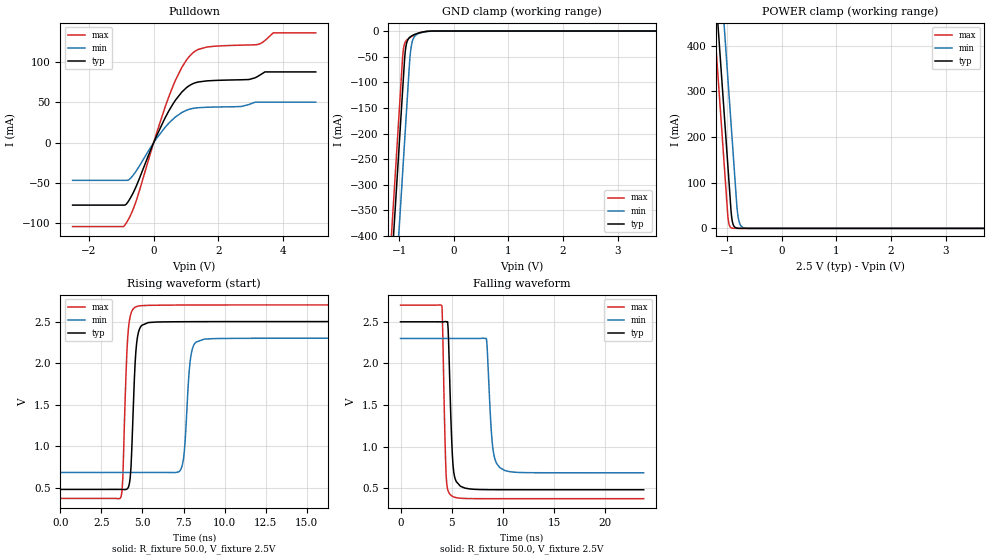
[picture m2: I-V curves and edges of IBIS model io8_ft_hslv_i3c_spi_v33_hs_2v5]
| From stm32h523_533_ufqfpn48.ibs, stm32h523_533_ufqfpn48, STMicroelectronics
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[Model]   io8_ft_hslv_i3c_spi_v33_hs_2v5
Model_type I/O_open_drain
Polarity   Non-Inverting
Enable   Active-Low
| CAP_THRESHOLD on pad IOFT is "UDTCAPC" :
| Rising=20.0% of vddiom   Falling=80.0% of vddiom
| C_comp min and max val. don't necessarily correlate with the min and max pvt
| but are the smallest and greatest pad capacitance found.
| var   typ   min   max
C_comp   3.86841pF  3.83550pF  3.96274pF
|C_comp_pulldown   3.86841pF  3.83550pF  3.96274pF
Vinl = 1.15V
Vinh = 1.35V
Vmeas = 1.25V   | Reference voltage for timing measurements
Cref  = 50.0pF   | Timing specification test load capacitance value
Rref  = 1.0MOhm   | Timing specification test load resistance value
Vref  = 1.375V   | Timing specification test load voltage
[Model Spec]
| TIME_THRESHOLD on pin ZII2CV11 is "CMOS" :
| Rising=40.0% of vdd   Falling=60.0% of vdd
Vinl 978.80000mV 906.80000mV 1.05480V
Vinh 1.39920V 1.29220V 1.48720V
| variable   typ   min   max
[Temperature Range] 25.0 125.0 -40.0
| variable   typ   min   max
[Voltage Range] 2.5V 2.3V 2.7V
| variable   typ   min   max
[POWER Clamp Reference] 2.5V 2.3V 2.7V
| variable   typ   min   max
[GND Clamp Reference] 0V 0V 0V
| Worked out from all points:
|   slope of the pulldown table from 0 to 0.375 V, typ, clamps not added: 11.5 ohm
|   GND clamp passes 1 mA (typ) near -0.52 V on its own axis
|   POWER clamp passes 1 mA (typ) near -0.84 V on its own axis
|   rising waveform, R_fixture 50.0, V_fixture 2.5V: 20-80 % time 253ps typ, 305ps min, 242ps max; typ from 0.481 V to 2.5 V
|   falling waveform, R_fixture 50.0, V_fixture 2.5V: 20-80 % time 336ps typ, 448ps min, 253ps max; typ from 2.5 V to 0.481 V
[POWER Clamp]
-2.5V     2.708A     2.899A     2.597A
-1.23V    548.8mA    740.2mA    437.5mA
-1.16V    429.8mA    621.2mA    318.5mA
-1.12V    361.8mA    553.2mA    250.5mA
-1.03V    208.8mA    400.2mA    97.53mA
-980mV    123.8mA    315.2mA    17.95mA
-920mV    26.3mA     213.2mA    906uA
-880mV    5.543mA    145.2mA    123.7uA
-810mV    363.5uA    33.6mA     3.797uA
-770mV    76.62uA    10.47mA    518.8nA
-700mV    5.026uA    1.361mA    16.09nA
5V        0A         0A         0A
[GND Clamp]
-2.5V     -2.77A     -2.931A    -2.704A
-1.21V    -576.8mA   -738.1mA   -511.3mA
-950mV    -134.8mA   -296.1mA   -69.34mA
-920mV    -83.82mA   -245.1mA   -32.48mA
-900mV    -50.56mA   -211.1mA   -24.02mA
-880mV    -31.31mA   -177.1mA   -19.85mA
-850mV    -18.7mA    -126.1mA   -16.34mA
-800mV    -11.46mA   -46.18mA   -12.45mA
-750mV    -8.203mA   -16.63mA   -9.325mA
-650mV    -4.063mA   -4.987mA   -4.427mA
-360mV    -35.05uA   -165.1uA   -9.564uA
5V        7.96nA     1.282uA    294pA
| variable   typ   min   max
[Pullup Reference] 2.5V 2.3V 2.7V
| variable   typ   min   max
[Pulldown Reference] 0V 0V 0V
[Pulldown]
-2.5V     -77.63mA   -46.85mA   -104.3mA
-870mV    -77.24mA   -46.85mA   -101.4mA
-550mV    -55.3mA    -35.88mA   -73.72mA
90mV      8.401mA    5.299mA    11.79mA
610mV     49.03mA    29.76mA    71.69mA
870mV     62.92mA    37.48mA    93.62mA
1.23V     73.63mA    42.72mA    112.2mA
1.64V     76.78mA    44.01mA    118.8mA
2.7V      78.15mA    44.99mA    121.2mA
3.22V     82.58mA    50.35mA    122.2mA
3.69V     87.93mA    50.35mA    136.5mA
5V        87.93mA    50.35mA    136.5mA
[Ramp]
dV/dt_r 1.21161V/248.6152ps 969.17876mV/301.03751ps 1.39625V/238.23257ps
dV/dt_f 1.21165V/333.92105ps 969.24844mV/447.8085ps 1.39628V/252.6168ps
R_load = 50.0
| Removed startup time: 0s 0s 0s  .
| Removed end time: 23.75ns.
[Rising Waveform]
R_fixture   = 50.0
V_fixture   = 2.5V
V_fixture_min = 2.3V
V_fixture_max = 2.7V
0s        480.6mV    684.6mV    372.9mV
3.7ns     480.6mV    684.6mV    397.6mV
3.8ns     480mV      684.6mV    613.6mV
4.1ns     494.1mV    684.6mV    2.314V
4.3ns     751.3mV    684.6mV    2.598V
4.6ns     2.15V      684.6mV    2.677V
7.35ns    2.498V     727.6mV    2.699V
7.9ns     2.498V     2.015V     2.699V
8.25ns    2.499V     2.251V     2.699V
23.75ns   2.5V       2.3V       2.7V
| Removed startup time: 0s 0s 0s  .
| Removed end time: 23.75ns.
[Falling Waveform]
R_fixture   = 50.0
V_fixture   = 2.5V
V_fixture_min = 2.3V
V_fixture_max = 2.7V
0s        2.5V       2.3V       2.7V
4.05ns    2.499V     2.3V       2.688V
4.45ns    2.503V     2.3V       669.2mV
4.65ns    2.419V     2.3V       466.7mV
4.95ns    1.23V      2.3V       411.4mV
5.45ns    578.1mV    2.3V       385mV
8.4ns     481.8mV    2.291V     373.1mV
8.95ns    481.2mV    1.06V      373mV
9.7ns     480.9mV    745.8mV    373mV
23.75ns   480.6mV    684.6mV    372.9mV
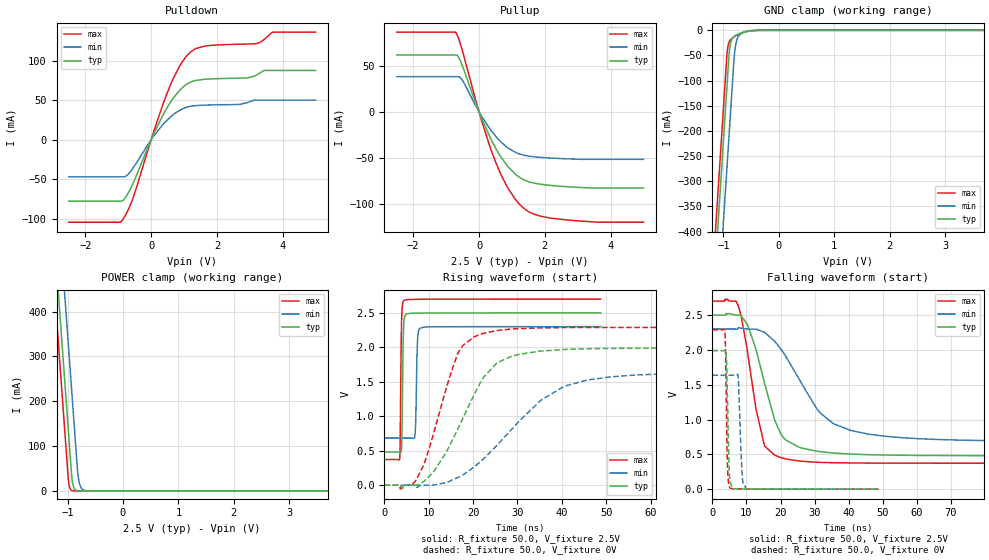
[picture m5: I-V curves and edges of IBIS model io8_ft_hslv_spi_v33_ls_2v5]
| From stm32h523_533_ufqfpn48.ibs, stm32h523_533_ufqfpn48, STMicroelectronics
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[Model]   io8_ft_hslv_spi_v33_ls_2v5
Model_type I/O
Polarity   Non-Inverting
Enable   Active-Low
| CAP_THRESHOLD on pad IOFT is "UDTCAPC" :
| Rising=20.0% of vddiom   Falling=80.0% of vddiom
| C_comp min and max val. don't necessarily correlate with the min and max pvt
| but are the smallest and greatest pad capacitance found.
| var   typ   min   max
C_comp   3.86826pF  3.83550pF  3.96274pF
|C_comp_pullup   2.45390pF  2.33570pF  2.34225pF
|C_comp_pulldown   1.41436pF  1.49980pF  1.62049pF
Vinl = 690.0mV
Vinh = 1.89V
Vmeas = 1.25V   | Reference voltage for timing measurements
Cref  = 50.0pF   | Timing specification test load capacitance value
Rref  = 100.0MOhm   | Timing specification test load resistance value
Vref  = 1.25V   | Timing specification test load voltage
[Model Spec]
| TIME_THRESHOLD on pin ZIV33M is "CMOS" :
| Rising=40.0% of vddiom   Falling=60.0% of vddiom
Vinl 978.80000mV 906.80000mV 1.05480V
Vinh 1.39920V 1.29220V 1.48720V
| variable   typ   min   max
[Temperature Range] 25.0 125.0 -40.0
| variable   typ   min   max
[Voltage Range] 2.5V 2.3V 2.7V
| variable   typ   min   max
[POWER Clamp Reference] 2.5V 2.3V 2.7V
| variable   typ   min   max
[GND Clamp Reference] 0V 0V 0V
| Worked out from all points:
|   slope of the pulldown table from 0 to 0.375 V, typ, clamps not added: 11.5 ohm
|   slope of the pullup table from 0 to 0.375 V, typ, clamps not added: 12.3 ohm
|   GND clamp passes 1 mA (typ) near -0.52 V on its own axis
|   POWER clamp passes 1 mA (typ) near -0.84 V on its own axis
|   rising waveform, R_fixture 50.0, V_fixture 2.5V: 20-80 % time 251ps typ, 301ps min, 240ps max; typ from 0.481 V to 2.5 V
|   falling waveform, R_fixture 50.0, V_fixture 2.5V: 20-80 % time 7.06ns typ, 13.2ns min, 4.9ns max; typ from 2.5 V to 0.481 V
|   rising waveform, R_fixture 50.0, V_fixture 0V: 20-80 % time 9.58ns typ, 15.8ns min, 6.38ns max; typ from 0 V to 1.99 V
|   falling waveform, R_fixture 50.0, V_fixture 0V: 20-80 % time 570ps typ, 766ps min, 453ps max; typ from 1.99 V to 0 V
[POWER Clamp]
-2.5V     2.708A     2.899A     2.597A
-1.23V    548.8mA    740.2mA    437.5mA
-1.16V    429.8mA    621.2mA    318.5mA
-1.12V    361.8mA    553.2mA    250.5mA
-1.03V    208.8mA    400.2mA    97.53mA
-980mV    123.8mA    315.2mA    17.95mA
-920mV    26.3mA     213.2mA    906uA
-880mV    5.543mA    145.2mA    123.7uA
-810mV    363.5uA    33.6mA     3.797uA
-770mV    76.62uA    10.47mA    518.8nA
-700mV    5.026uA    1.361mA    16.09nA
5V        0A         0A         0A
[GND Clamp]
-2.5V     -2.77A     -2.931A    -2.704A
-1.21V    -576.8mA   -738.1mA   -511.3mA
-950mV    -134.8mA   -296.1mA   -69.34mA
-920mV    -83.82mA   -245.1mA   -32.48mA
-900mV    -50.56mA   -211.1mA   -24.02mA
-880mV    -31.31mA   -177.1mA   -19.85mA
-850mV    -18.7mA    -126.1mA   -16.34mA
-800mV    -11.46mA   -46.18mA   -12.45mA
-750mV    -8.203mA   -16.63mA   -9.325mA
-650mV    -4.063mA   -4.987mA   -4.427mA
-360mV    -35.05uA   -165.1uA   -9.564uA
5V        7.96nA     1.281uA    294pA
| variable   typ   min   max
[Pullup Reference] 2.5V 2.3V 2.7V
| variable   typ   min   max
[Pulldown Reference] 0V 0V 0V
[Pullup]
-2.5V     61.52mA    38.03mA    86.31mA
-700mV    61.52mA    38.03mA    85.53mA
-620mV    58.98mA    38.03mA    79.33mA
-510mV    50.24mA    34.32mA    66.72mA
90mV      -7.98mA    -5.461mA   -10.94mA
510mV     -39.75mA   -26.71mA   -54.98mA
870mV     -59.15mA   -39.06mA   -82.32mA
1.13V     -68.49mA   -44.46mA   -96.16mA
1.38V     -74.01mA   -47.22mA   -105.1mA
1.86V     -78.47mA   -49.41mA   -113mA
2.42V     -80.56mA   -50.6mA    -116.3mA
5V        -82.59mA   -51.55mA   -119.6mA
[Pulldown]
-2.5V     -77.63mA   -46.85mA   -104.3mA
-870mV    -77.24mA   -46.85mA   -101.4mA
-550mV    -55.3mA    -35.88mA   -73.72mA
90mV      8.401mA    5.299mA    11.79mA
610mV     49.03mA    29.75mA    71.69mA
870mV     62.92mA    37.48mA    93.62mA
1.23V     73.63mA    42.72mA    112.2mA
1.64V     76.78mA    44.01mA    118.8mA
2.7V      78.15mA    44.99mA    121.2mA
3.22V     82.58mA    50.35mA    122.2mA
3.69V     87.93mA    50.35mA    136.5mA
5V        87.93mA    50.35mA    136.5mA
[Ramp]
dV/dt_r 1.19372V/9.38252ns 981.15077mV/15.45894ns 1.37325V/6.30898ns
dV/dt_f 1.21165V/6.77971ns 969.25365mV/12.85547ns 1.39628V/4.50815ns
R_load = 50.0
| Removed startup time: 0s 0s 0s  .
| Removed end time: 48.75ns.
[Rising Waveform]
R_fixture   = 50.0
V_fixture   = 2.5V
V_fixture_min = 2.3V
V_fixture_max = 2.7V
0s        480.6mV    684.6mV    372.9mV
3.45ns    481mV      684.6mV    396.9mV
3.85ns    538.7mV    684.6mV    2.335V
4.25ns    2.146V     684.6mV    2.666V
4.45ns    2.405V     684.6mV    2.681V
6.85ns    2.496V     711.1mV    2.695V
7.05ns    2.496V     923mV      2.696V
7.45ns    2.496V     2.085V     2.696V
7.95ns    2.497V     2.276V     2.696V
48.75ns   2.5V       2.3V       2.7V
| Removed startup time: 0s 0s 0s  .
| Removed end time: 248.75ns.
[Falling Waveform]
R_fixture   = 50.0
V_fixture   = 2.5V
V_fixture_min = 2.3V
V_fixture_max = 2.7V
0s        2.5V       2.3V       2.7V
7.05ns    2.5V       2.3V       2.692V
10.4ns    2.349V     2.3V       1.94V
12.8ns    2.009V     2.299V     1.152V
15.25ns   1.534V     2.253V     629.7mV
18.3ns    988.4mV    2.124V     486.9mV
21.5ns    706.4mV    1.91V      434.6mV
35.55ns   518.9mV    938.9mV    379.6mV
50.8ns    490mV      759.1mV    373.8mV
248.8ns   480.6mV    684.6mV    372.9mV
| Removed startup time: 0s 0s 0s  .
| Removed end time: 248.7ns.
[Rising Waveform]
R_fixture   = 50.0
V_fixture   = 0V
V_fixture_min = 0V
V_fixture_max = 0V
0s        168.9nV    416.7nV    134.4nV
6.6ns     -463.7uV   -2.194mV   31.15mV
8.9ns     55.55mV    -749.9uV   301.1mV
11ns      185.7mV    1.592mV    731.9mV
17.1ns    891.5mV    127.4mV    1.975V
22.4ns    1.57V      385.5mV    2.204V
25.4ns    1.776V     580.8mV    2.243V
40.6ns    1.969V     1.436V     2.286V
55.9ns    1.987V     1.595V     2.289V
248.7ns   1.99V      1.635V     2.289V
| Removed startup time: 0s 0s 0s  .
| Removed end time: 48.75ns.
[Falling Waveform]
R_fixture   = 50.0
V_fixture   = 0V
V_fixture_min = 0V
V_fixture_max = 0V
0s        1.99V      1.635V     2.289V
3.65ns    1.99V      1.635V     2.292V
4.05ns    1.963V     1.635V     1.439V
4.45ns    1.266V     1.635V     314.6mV
4.85ns    406.3mV    1.635V     58.74mV
5.2ns     99.19mV    1.635V     16.82mV
7.5ns     2.995mV    1.642V     3.887mV
8.75ns    2.803mV    200.1mV    3.096mV
9.95ns    2.66mV     5.047mV    1.678mV
48.75ns   42.19uV    126.7uV    16.77uV
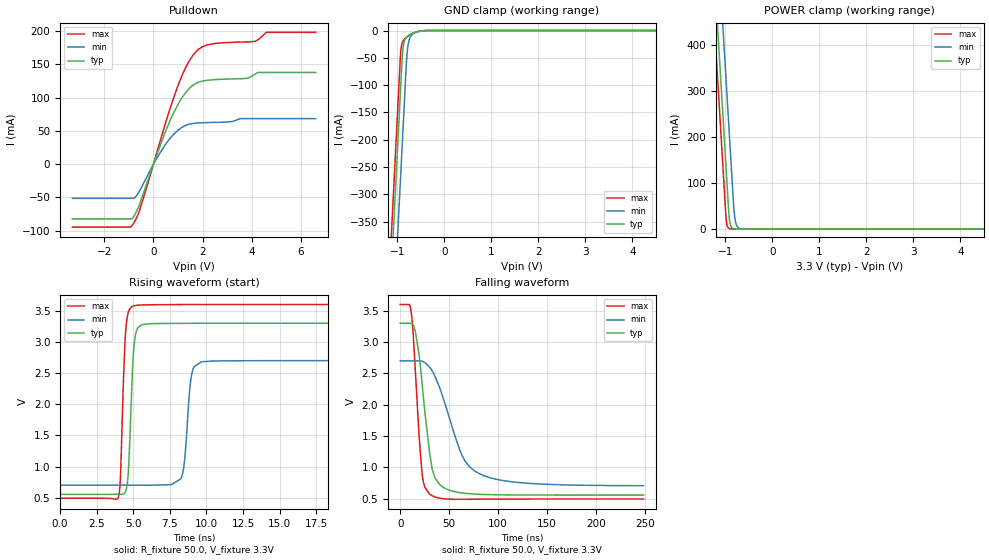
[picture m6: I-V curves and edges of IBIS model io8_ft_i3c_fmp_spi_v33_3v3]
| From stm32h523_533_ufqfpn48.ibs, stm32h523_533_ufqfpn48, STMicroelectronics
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[Model]   io8_ft_i3c_fmp_spi_v33_3v3
Model_type I/O_open_drain
Polarity   Non-Inverting
Enable   Active-Low
| CAP_THRESHOLD on pad IOFT is "UDTCAPC" :
| Rising=20.0% of vddiom   Falling=80.0% of vddiom
| C_comp min and max val. don't necessarily correlate with the min and max pvt
| but are the smallest and greatest pad capacitance found.
| var   typ   min   max
C_comp   3.95297pF  3.95017pF  4.00762pF
|C_comp_pulldown   3.95297pF  3.95017pF  4.00762pF
Vinl = 1.35V
Vinh = 1.8V
Vmeas = 1.65V   | Reference voltage for timing measurements
Cref  = 50.0pF   | Timing specification test load capacitance value
Rref  = 1.0MOhm   | Timing specification test load resistance value
Vref  = 1.815V   | Timing specification test load voltage
[Model Spec]
| TIME_THRESHOLD on pin ZII2CV11 is "CMOS" :
| Rising=40.0% of vdd   Falling=60.0% of vdd
Vinl 1.28680V 1.06380V 1.39380V
Vinh 1.76920V 1.48820V 1.89120V
| variable   typ   min   max
[Temperature Range] 25.0 125.0 -40.0
| variable   typ   min   max
[Voltage Range] 3.3V 2.7V 3.6V
| variable   typ   min   max
[POWER Clamp Reference] 3.3V 2.7V 3.6V
| variable   typ   min   max
[GND Clamp Reference] 0V 0V 0V
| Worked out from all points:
|   slope of the pulldown table from 0 to 0.495 V, typ, clamps not added: 10 ohm
|   GND clamp passes 1 mA (typ) near -0.52 V on its own axis
|   POWER clamp passes 1 mA (typ) near -0.84 V on its own axis
|   rising waveform, R_fixture 50.0, V_fixture 3.3V: 20-80 % time 285ps typ, 380ps min, 266ps max; typ from 0.556 V to 3.3 V
|   falling waveform, R_fixture 50.0, V_fixture 3.3V: 20-80 % time 11.7ns typ, 26.6ns min, 7.34ns max; typ from 3.3 V to 0.556 V
[POWER Clamp]
-3.3V     4.068A     4.259A     3.957A
-1.25V    582.8mA    774.2mA    471.5mA
-1.21V    514.8mA    706.2mA    403.5mA
-1.13V    378.8mA    570.2mA    267.5mA
-1.04V    225.8mA    417.2mA    114.5mA
-980mV    123.8mA    315.2mA    17.95mA
-920mV    26.3mA     213.2mA    906uA
-880mV    5.543mA    145.2mA    123.7uA
-810mV    363.5uA    33.6mA     3.798uA
-770mV    76.62uA    10.47mA    519.4nA
-690mV    3.409uA    1.017mA    10.46nA
6.6V      0A         0A         0A
[GND Clamp]
-3.3V     -4.13A     -4.291A    -4.063A
-1.25V    -644.7mA   -806.4mA   -578.1mA
-940mV    -117.7mA   -279.4mA   -51.06mA
-920mV    -83.75mA   -245.4mA   -31.43mA
-900mV    -50.5mA    -211.4mA   -23.14mA
-880mV    -31.27mA   -177.4mA   -19.1mA
-850mV    -18.68mA   -126.4mA   -15.73mA
-800mV    -11.46mA   -46.4mA    -12.03mA
-760mV    -8.752mA   -20.02mA   -9.606mA
-680mV    -5.122mA   -6.673mA   -5.579mA
-300mV    -5.379uA   -47.63uA   -852.7nA
6.6V      10.49nA    1.843uA    393.6pA
| variable   typ   min   max
[Pullup Reference] 3.3V 2.7V 3.6V
| variable   typ   min   max
[Pulldown Reference] 0V 0V 0V
[Pulldown]
-3.3V     -82.42mA   -51.49mA   -94.82mA
-850mV    -81.27mA   -51.49mA   -91.26mA
-580mV    -62.01mA   -41.36mA   -71.41mA
120mV     12.61mA    7.999mA    15.37mA
800mV     75.3mA     43.94mA    97.52mA
1.33V     108.3mA    58.37mA    146.5mA
1.84V     123.1mA    61.83mA    172.7mA
2.51V     126.9mA    62.69mA    181.3mA
3.78V     128.8mA    68.32mA    183.7mA
4.12V     134.9mA    68.32mA    184.6mA
4.59V     137.6mA    68.32mA    198mA
6.6V      137.6mA    68.32mA    198mA
[Ramp]
dV/dt_r 1.64663V/282.83482ps 1.19796V/377.68906ps 1.86385V/262.65072ps
dV/dt_f 1.64665V/11.53534ns 1.19655V/26.44587ns 1.86387V/7.2722ns
R_load = 50.0
| Removed startup time: 0s 0s 0s  .
| Removed end time: 33.7ns.
[Rising Waveform]
R_fixture   = 50.0
V_fixture   = 3.3V
V_fixture_min = 2.7V
V_fixture_max = 3.6V
0s        555.6mV    703.3mV    493.6mV
3.95ns    557.8mV    703.3mV    494.7mV
4.1ns     556.7mV    703.3mV    727.6mV
4.4ns     575.5mV    703.3mV    2.843V
4.6ns     741.7mV    703.3mV    3.417V
5ns       2.797V     703.3mV    3.576V
8.25ns    3.298V     803mV      3.599V
8.95ns    3.298V     2.425V     3.599V
9.65ns    3.299V     2.681V     3.6V
33.7ns    3.3V       2.7V       3.6V
| Removed startup time: 0s 0s 0s  .
| Removed end time: 248.75ns.
[Falling Waveform]
R_fixture   = 50.0
V_fixture   = 3.3V
V_fixture_min = 2.7V
V_fixture_max = 3.6V
0s        3.3V       2.7V       3.6V
11.05ns   3.3V       2.7V       3.492V
15.35ns   3.178V     2.7V       2.556V
22.2ns    2.362V     2.694V     927.6mV
30.45ns   1.183V     2.593V     567.7mV
35.55ns   827.1mV    2.453V     525.4mV
41.9ns    701.4mV    2.201V     502mV
62.75ns   591.3mV    1.205V     488.3mV
81.25ns   568.7mV    894.5mV    490.6mV
248.8ns   555.6mV    705.7mV    493.6mV
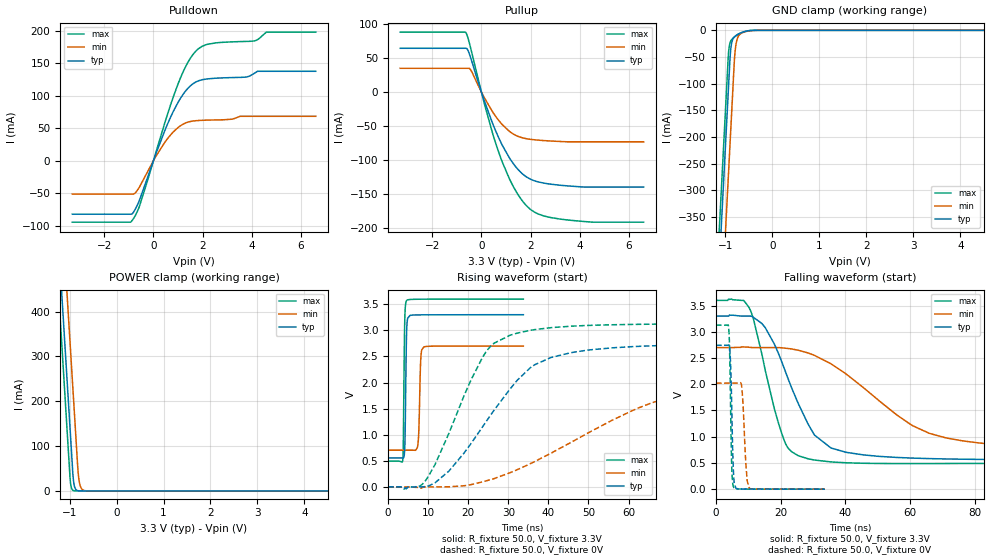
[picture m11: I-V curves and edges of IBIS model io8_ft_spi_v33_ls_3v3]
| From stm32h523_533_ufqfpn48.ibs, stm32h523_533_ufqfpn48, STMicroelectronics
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[Model]   io8_ft_spi_v33_ls_3v3
Model_type I/O
Polarity   Non-Inverting
Enable   Active-Low
| CAP_THRESHOLD on pad IOFT is "UDTCAPC" :
| Rising=20.0% of vddiom   Falling=80.0% of vddiom
| C_comp min and max val. don't necessarily correlate with the min and max pvt
| but are the smallest and greatest pad capacitance found.
| var   typ   min   max
C_comp   3.95292pF  3.95016pF  4.00762pF
|C_comp_pullup   2.45805pF  2.54070pF  2.38980pF
|C_comp_pulldown   1.49487pF  1.40946pF  1.61782pF
Vinl = 810.0mV
Vinh = 2.52V
Vmeas = 1.65V   | Reference voltage for timing measurements
Cref  = 50.0pF   | Timing specification test load capacitance value
Rref  = 100.0MOhm   | Timing specification test load resistance value
Vref  = 1.65V   | Timing specification test load voltage
[Model Spec]
| TIME_THRESHOLD on pin ZIV33M is "CMOS" :
| Rising=40.0% of vddiom   Falling=60.0% of vddiom
Vinl 1.28680V 1.06380V 1.39380V
Vinh 1.76920V 1.48820V 1.89120V
| variable   typ   min   max
[Temperature Range] 25.0 125.0 -40.0
| variable   typ   min   max
[Voltage Range] 3.3V 2.7V 3.6V
| variable   typ   min   max
[POWER Clamp Reference] 3.3V 2.7V 3.6V
| variable   typ   min   max
[GND Clamp Reference] 0V 0V 0V
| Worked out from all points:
|   slope of the pulldown table from 0 to 0.495 V, typ, clamps not added: 10 ohm
|   slope of the pullup table from 0 to 0.495 V, typ, clamps not added: 10 ohm
|   GND clamp passes 1 mA (typ) near -0.52 V on its own axis
|   POWER clamp passes 1 mA (typ) near -0.84 V on its own axis
|   rising waveform, R_fixture 50.0, V_fixture 3.3V: 20-80 % time 290ps typ, 392ps min, 266ps max; typ from 0.556 V to 3.3 V
|   falling waveform, R_fixture 50.0, V_fixture 3.3V: 20-80 % time 11.6ns typ, 26.8ns min, 7.44ns max; typ from 3.3 V to 0.556 V
|   rising waveform, R_fixture 50.0, V_fixture 0V: 20-80 % time 16.4ns typ, 31.6ns min, 10.9ns max; typ from 0 V to 2.74 V
|   falling waveform, R_fixture 50.0, V_fixture 0V: 20-80 % time 654ps typ, 987ps min, 524ps max; typ from 2.74 V to 0 V
[POWER Clamp]
-3.3V     4.068A     4.259A     3.957A
-1.25V    582.8mA    774.2mA    471.5mA
-1.21V    514.8mA    706.2mA    403.5mA
-1.13V    378.8mA    570.2mA    267.5mA
-1.04V    225.8mA    417.2mA    114.5mA
-980mV    123.8mA    315.2mA    17.95mA
-920mV    26.3mA     213.2mA    906uA
-880mV    5.543mA    145.2mA    123.7uA
-810mV    363.5uA    33.6mA     3.798uA
-770mV    76.62uA    10.47mA    519.4nA
-690mV    3.409uA    1.017mA    10.46nA
6.6V      0A         0A         0A
[GND Clamp]
-3.3V     -4.13A     -4.291A    -4.063A
-1.25V    -644.7mA   -806.4mA   -578.1mA
-940mV    -117.7mA   -279.4mA   -51.06mA
-920mV    -83.75mA   -245.4mA   -31.43mA
-900mV    -50.5mA    -211.4mA   -23.14mA
-880mV    -31.27mA   -177.4mA   -19.1mA
-850mV    -18.68mA   -126.4mA   -15.73mA
-800mV    -11.46mA   -46.4mA    -12.03mA
-760mV    -8.752mA   -20.02mA   -9.606mA
-680mV    -5.122mA   -6.673mA   -5.579mA
-320mV    -10.25uA   -73.91uA   -1.981uA
6.6V      10.49nA    1.843uA    393.6pA
| variable   typ   min   max
[Pullup Reference] 3.3V 2.7V 3.6V
| variable   typ   min   max
[Pulldown Reference] 0V 0V 0V
[Pullup]
-3.3V     64.14mA    34.79mA    87.88mA
-630mV    64.14mA    34.79mA    87.06mA
-550mV    61.28mA    34.79mA    79.76mA
-430mV    49.66mA    32.11mA    63.57mA
120mV     -12.97mA   -8.371mA   -17mA
470mV     -47.32mA   -29.82mA   -62.25mA
800mV     -74.37mA   -45.77mA   -97.83mA
1.43V     -111mA     -64.06mA   -146.9mA
2.03V     -128.3mA   -69.46mA   -173mA
2.51V     -133.3mA   -71.08mA   -181.3mA
3.53V     -137.6mA   -72.97mA   -187.6mA
6.6V      -139.3mA   -72.97mA   -190.8mA
[Pulldown]
-3.3V     -82.42mA   -51.49mA   -94.82mA
-850mV    -81.27mA   -51.49mA   -91.26mA
-580mV    -62.01mA   -41.36mA   -71.41mA
120mV     12.61mA    7.999mA    15.37mA
800mV     75.3mA     43.94mA    97.52mA
1.33V     108.3mA    58.37mA    146.5mA
1.84V     123.1mA    61.83mA    172.7mA
2.51V     126.9mA    62.69mA    181.3mA
3.78V     128.8mA    68.32mA    183.7mA
4.12V     134.9mA    68.32mA    184.6mA
4.59V     137.6mA    68.32mA    198mA
6.6V      137.6mA    68.32mA    198mA
[Ramp]
dV/dt_r 1.6465V/16.17079ns 1.21245V/31.59838ns 1.87653V/10.77759ns
dV/dt_f 1.64665V/11.5353ns 1.19661V/26.44863ns 1.86387V/7.27211ns
R_load = 50.0
| Removed startup time: 0s 0s 0s  .
| Removed end time: 33.75ns.
[Rising Waveform]
R_fixture   = 50.0
V_fixture   = 3.3V
V_fixture_min = 2.7V
V_fixture_max = 3.6V
0s        555.6mV    703.3mV    493.6mV
3.65ns    552.7mV    703.3mV    510.7mV
3.8ns     553.3mV    703.3mV    826.9mV
4.15ns    721.5mV    703.3mV    3.146V
4.65ns    3.012V     703.3mV    3.573V
7.4ns     3.296V     790.1mV    3.596V
7.7ns     3.296V     1.136V     3.597V
8.2ns     3.297V     2.499V     3.597V
8.95ns    3.298V     2.684V     3.597V
33.75ns   3.3V       2.699V     3.6V
| Removed startup time: 0s 0s 0s  .
| Removed end time: 248.75ns.
[Falling Waveform]
R_fixture   = 50.0
V_fixture   = 3.3V
V_fixture_min = 2.7V
V_fixture_max = 3.6V
0s        3.3V       2.7V       3.6V
10.15ns   3.299V     2.707V     3.471V
15.25ns   3.077V     2.7V       2.259V
21.15ns   2.295V     2.69V      920.9mV
28.45ns   1.245V     2.598V     579.6mV
35.55ns   785.5mV    2.391V     519.8mV
39.9ns    708.2mV    2.211V     504.2mV
60.95ns   592.1mV    1.206V     488.3mV
76.15ns   571.5mV    922.1mV    490.1mV
248.8ns   555.6mV    705.6mV    493.6mV
| Removed startup time: 0s 0s 0s  .
| Removed end time: 248.7ns.
[Rising Waveform]
R_fixture   = 50.0
V_fixture   = 0V
V_fixture_min = 0V
V_fixture_max = 0V
0s        229.8nV    418.1nV    214.5nV
7.9ns     -510.9uV   -17.32mV   17.32mV
11.7ns    76.98mV    -361.4uV   425.3mV
24.4ns    1.244V     114.3mV    2.583V
35.5ns    2.284V     444.6mV    3.001V
45.7ns    2.573V     855.4mV    3.08V
62.4ns    2.693V     1.511V     3.115V
81.2ns    2.728V     1.851V     3.124V
126.9ns   2.743V     1.996V     3.127V
248.7ns   2.744V     2.021V     3.128V
| Removed startup time: 0s 0s 0s  .
| Removed end time: 33.7ns.
[Falling Waveform]
R_fixture   = 50.0
V_fixture   = 0V
V_fixture_min = 0V
V_fixture_max = 0V
0s        2.744V     2.021V     3.128V
3.9ns     2.75V      2.021V     3.085V
4.2ns     2.701V     2.021V     2.681V
4.85ns    1.616V     2.021V     463.4mV
5.2ns     674.8mV    2.021V     102.5mV
5.55ns    175.8mV    2.021V     27.06mV
7.9ns     2.936mV    1.979V     3.318mV
9.2ns     2.217mV    516.1mV    2.645mV
10.35ns   1.85mV     15.53mV    2.38mV
33.7ns    222.5uV    516.1uV    160.7uV
